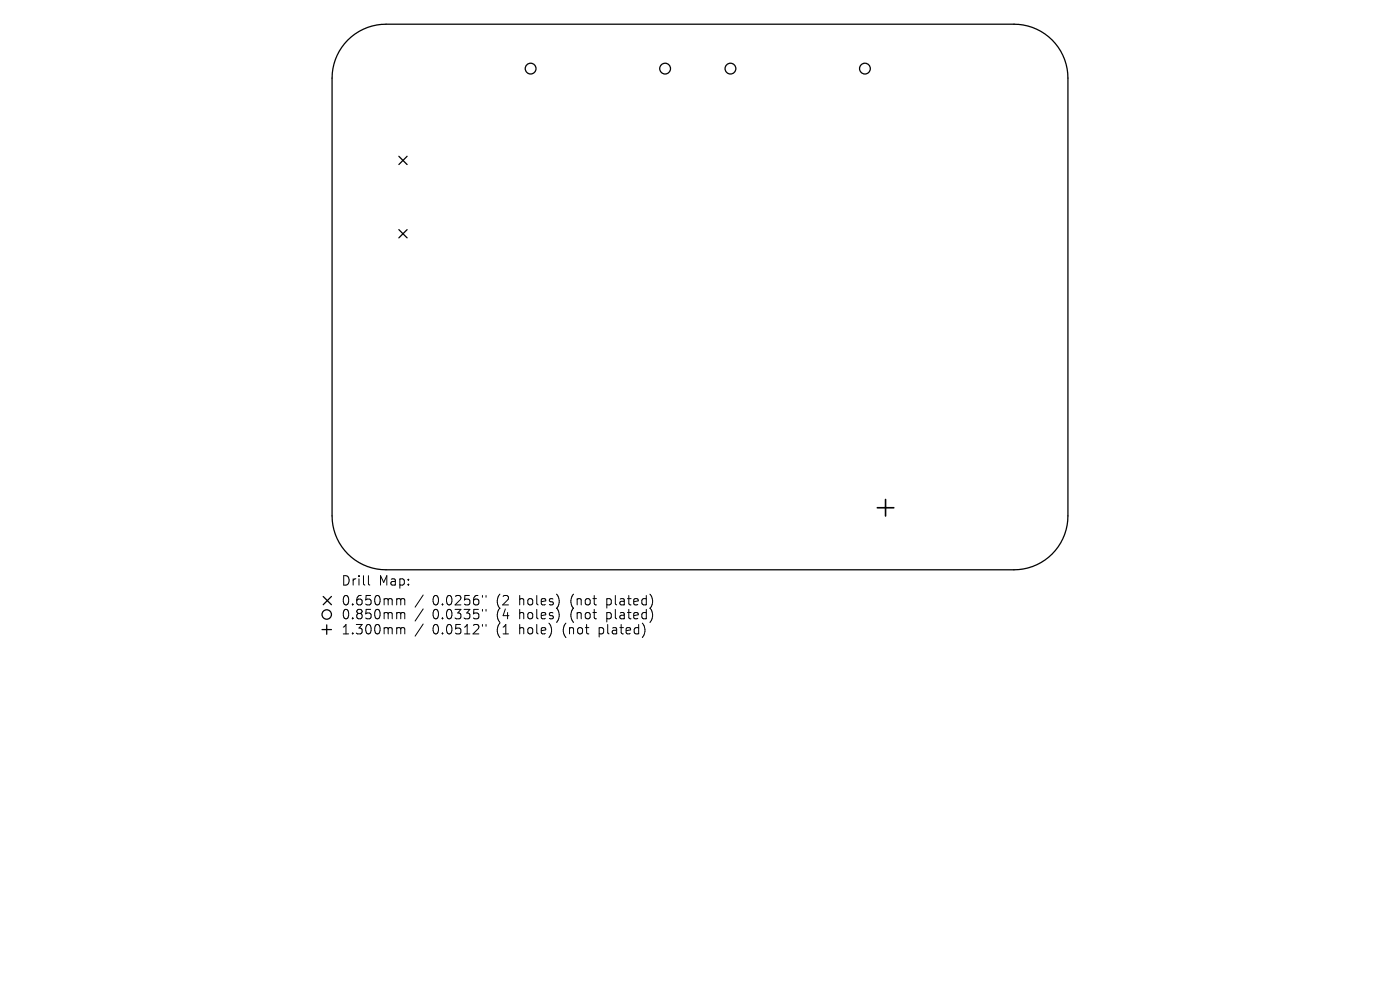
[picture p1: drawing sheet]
<svg xmlns="http://www.w3.org/2000/svg" width="297mm" height="210mm" viewBox="0 0 297 210" stroke-linecap="round" stroke-linejoin="round" font-family="sans-serif">
<defs><g id="words">
<g font-size="2.8">
<text x="72.3" y="124.5">Drill</text>
<text x="80.3" y="124.5">Map:</text>
<text x="72.3" y="128.7">0.650mm</text>
<text x="72.3" y="131.7">0.850mm</text>
<text x="91.8" y="128.7">0.0256&quot;</text>
<text x="91.8" y="131.7">0.0335&quot;</text>
<text x="105.5" y="128.7">(2</text>
<text x="105.5" y="131.7">(4</text>
<text x="110.4" y="128.7">holes)</text>
<text x="110.4" y="131.7">holes)</text>
<text x="121.5" y="128.7">(not</text>
<text x="121.5" y="131.7">(not</text>
<text x="129.3" y="128.7">plated)</text>
<text x="129.3" y="131.7">plated)</text>
<text x="72.3" y="134.9">1.300mm</text>
<text x="91.8" y="134.9">0.0512&quot;</text>
<text x="105.5" y="134.9">(1</text>
<text x="110.4" y="134.9">hole)</text>
<text x="119.9" y="134.9">(not</text>
<text x="127.7" y="134.9">plated)</text>
</g>
</g></defs>
<g fill="none" stroke="#000" stroke-width=".27">
<path d="M73.8 8.5a11.4 11.4 0 0 1 8.1-3.4h133.2a11.4 11.4 0 0 1 11.5 11.5v92.8a11.4 11.4 0 0 1-11.5 11.5h-133.2a11.4 11.4 0 0 1-11.5-11.5v-92.8a11.4 11.4 0 0 1 3.4-8.1zM84.6 33.2l1.8 1.7M86.4 33.2l-1.8 1.7M84.6 48.7l1.8 1.8M86.4 48.7l-1.8 1.8M68.3 133.6h2M68.6 126.5l1.7 1.8M69.3 132.6v2M70.3 126.5l-1.7 1.8"/>
<circle cx="112.6" cy="14.6" r="1.14"/>
<circle cx="141.1" cy="14.6" r="1.14"/>
<circle cx="155" cy="14.6" r="1.14"/>
<circle cx="183.5" cy="14.6" r="1.14"/>
<circle cx="69.3" cy="130.4" r="1"/>
</g>
<path d="M186.1 107.7h3.5M187.9 106v3.5" fill="none" stroke="#000" stroke-width=".35"/>
<g fill="none" stroke="#000" stroke-width=".21">
<path d="M78.2 122.1v1.7l.2 .3M84.4 127l.5 .1 .1 .2M84.4 129.9h.3l.3 .3M84.4 133.1h.3l.3 .3M85 127.3l.3-.3 .5 .1 .1 1.2M85 127.3v1M85 130.2v1.1M85 133.4v1.1M85 130.2l.3-.3 .5 .1 .1 1.3M85 133.4l.3-.3 .5 .1 .1 1.3M89.8 126.2l-1.7 2.6M89.8 129.2l-1.7 2.5"/>
<path d="M89.8 132.4l-1.7 2.5M102.3 126.3v.4M102.3 129.3v.3M102.3 132.5v.3M103.1 126.3v.4M103.1 129.3v.3M103.1 132.5v.3"/>
</g>
<use href="#words"/>
</svg>
